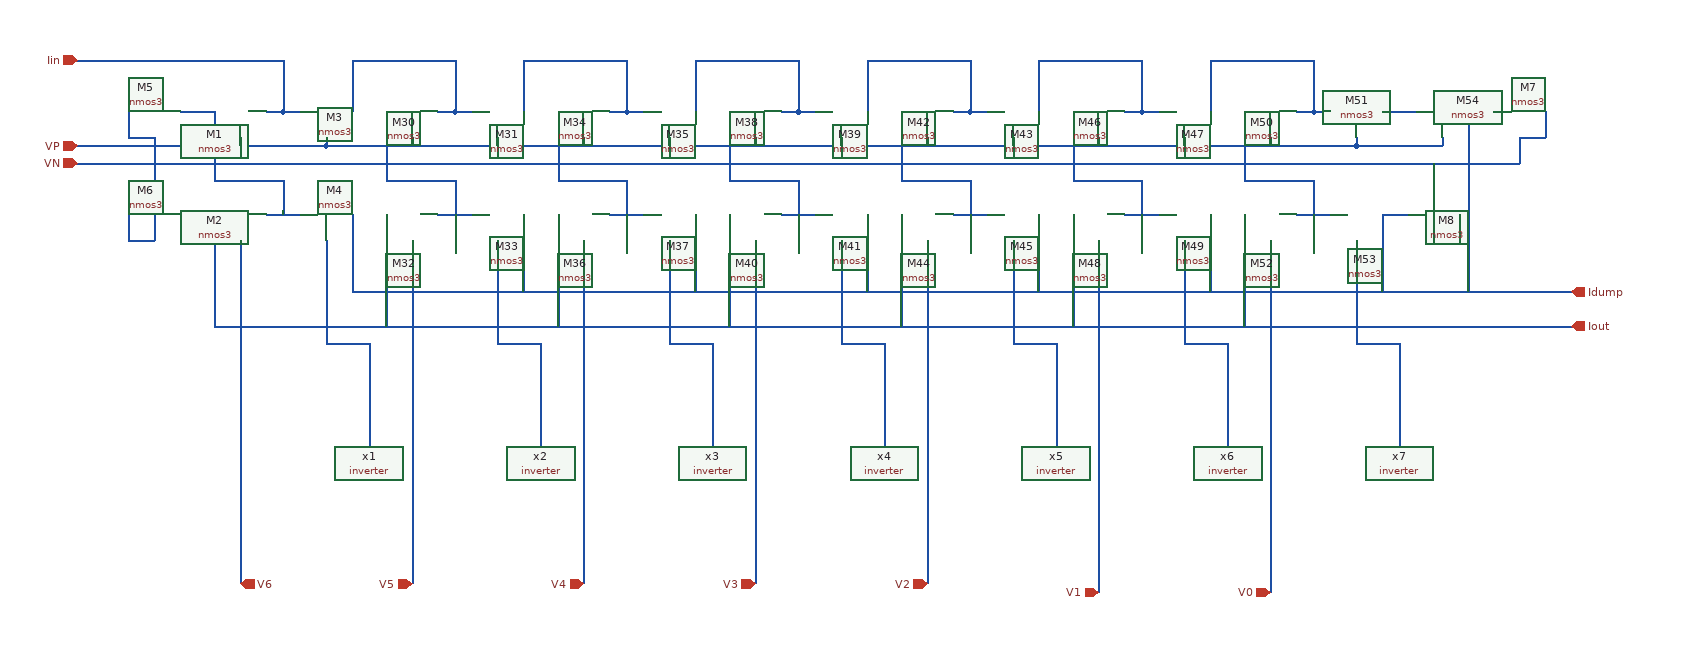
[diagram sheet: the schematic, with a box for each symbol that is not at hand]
v {xschem version=3.4.3 file_version=1.2
}
G {}
K {}
V {}
S {}
E {}
N 650 -40 650 -30 {
lab=V4}
N 250 -30 250 140 {
lab=V6}
N 450 -30 450 140 {
lab=V5}
N 650 -30 650 140 {
lab=V4}
N 850 -30 850 140 {
lab=V3}
N 1050 -30 1050 130 {
lab=V2}
N 1250 -30 1250 130 {
lab=V1}
N 1450 -30 1450 130 {
lab=V0}
N 1050 130 1050 140 {
lab=V2}
N 1250 130 1250 150 {
lab=V1}
N 1450 130 1450 150 {
lab=V0}
N 160 -370 350 -370 {
lab=VP}
N 350 -380 350 -370 {
lab=VP}
N 250 -380 250 -370 {
lab=VP}
N 160 -470 300 -470 {
lab=Iin}
N 300 -470 300 -410 {
lab=Iin}
N 280 -410 300 -410 {
lab=Iin}
N 300 -410 320 -410 {
lab=Iin}
N 280 -290 320 -290 {
lab=#net1}
N 220 -410 220 -330 {
lab=#net1}
N 220 -330 300 -330 {
lab=#net1}
N 300 -330 300 -290 {
lab=#net1}
N 550 -380 550 -370 {
lab=VP}
N 450 -380 450 -370 {
lab=VP}
N 500 -470 500 -410 {
lab=#net2}
N 480 -410 500 -410 {
lab=#net2}
N 500 -410 520 -410 {
lab=#net2}
N 480 -290 520 -290 {
lab=#net3}
N 420 -410 420 -330 {
lab=#net3}
N 420 -330 500 -330 {
lab=#net3}
N 500 -330 500 -290 {
lab=#net3}
N 450 -260 450 -240 {
lab=V5}
N 550 -260 550 -240 {
lab=#net4}
N 380 -470 380 -410 {
lab=#net2}
N 380 -470 500 -470 {
lab=#net2}
N 750 -380 750 -370 {
lab=VP}
N 650 -380 650 -370 {
lab=VP}
N 700 -470 700 -410 {
lab=#net5}
N 680 -410 700 -410 {
lab=#net5}
N 700 -410 720 -410 {
lab=#net5}
N 680 -290 720 -290 {
lab=#net6}
N 620 -410 620 -330 {
lab=#net6}
N 620 -330 700 -330 {
lab=#net6}
N 700 -330 700 -290 {
lab=#net6}
N 650 -260 650 -240 {
lab=V4}
N 750 -260 750 -240 {
lab=#net7}
N 580 -470 580 -410 {
lab=#net5}
N 580 -470 700 -470 {
lab=#net5}
N 950 -380 950 -370 {
lab=VP}
N 850 -380 850 -370 {
lab=VP}
N 900 -470 900 -410 {
lab=#net8}
N 880 -410 900 -410 {
lab=#net8}
N 900 -410 920 -410 {
lab=#net8}
N 880 -290 920 -290 {
lab=#net9}
N 820 -410 820 -330 {
lab=#net9}
N 820 -330 900 -330 {
lab=#net9}
N 900 -330 900 -290 {
lab=#net9}
N 850 -260 850 -240 {
lab=V3}
N 950 -260 950 -240 {
lab=#net10}
N 780 -470 780 -410 {
lab=#net8}
N 780 -470 900 -470 {
lab=#net8}
N 1150 -380 1150 -370 {
lab=VP}
N 1050 -380 1050 -370 {
lab=VP}
N 1100 -470 1100 -410 {
lab=#net11}
N 1080 -410 1100 -410 {
lab=#net11}
N 1100 -410 1120 -410 {
lab=#net11}
N 1080 -290 1120 -290 {
lab=#net12}
N 1020 -410 1020 -330 {
lab=#net12}
N 1020 -330 1100 -330 {
lab=#net12}
N 1100 -330 1100 -290 {
lab=#net12}
N 1050 -260 1050 -240 {
lab=V2}
N 1150 -260 1150 -240 {
lab=#net13}
N 980 -470 980 -410 {
lab=#net11}
N 980 -470 1100 -470 {
lab=#net11}
N 1350 -380 1350 -370 {
lab=VP}
N 1250 -380 1250 -370 {
lab=VP}
N 1300 -470 1300 -410 {
lab=#net14}
N 1280 -410 1300 -410 {
lab=#net14}
N 1300 -410 1320 -410 {
lab=#net14}
N 1280 -290 1320 -290 {
lab=#net15}
N 1220 -410 1220 -330 {
lab=#net15}
N 1220 -330 1300 -330 {
lab=#net15}
N 1300 -330 1300 -290 {
lab=#net15}
N 1250 -260 1250 -240 {
lab=V1}
N 1350 -260 1350 -240 {
lab=#net16}
N 1180 -470 1180 -410 {
lab=#net14}
N 1180 -470 1300 -470 {
lab=#net14}
N 1550 -380 1550 -370 {
lab=VP}
N 1450 -380 1450 -370 {
lab=VP}
N 1500 -470 1500 -410 {
lab=#net17}
N 1480 -410 1500 -410 {
lab=#net17}
N 1500 -410 1520 -410 {
lab=#net17}
N 1480 -290 1520 -290 {
lab=#net18}
N 1420 -410 1420 -330 {
lab=#net18}
N 1420 -330 1500 -330 {
lab=#net18}
N 1500 -330 1500 -290 {
lab=#net18}
N 1450 -260 1450 -240 {
lab=V0}
N 1550 -260 1550 -240 {
lab=#net19}
N 1380 -470 1380 -410 {
lab=#net17}
N 1380 -470 1500 -470 {
lab=#net17}
N 350 -370 1550 -370 {
lab=VP}
N 380 -290 380 -200 {
lab=Idump}
N 380 -200 1620 -200 {
lab=Idump}
N 220 -290 220 -160 {
lab=Iout}
N 350 -260 350 -240 {
lab=#net20}
N 250 -260 250 -240 {
lab=V6}
N 580 -290 580 -200 {
lab=Idump}
N 420 -290 420 -160 {
lab=Iout}
N 780 -290 780 -200 {
lab=Idump}
N 620 -290 620 -160 {
lab=Iout}
N 820 -290 820 -160 {
lab=Iout}
N 980 -290 980 -200 {
lab=Idump}
N 1020 -290 1020 -160 {
lab=Iout}
N 1180 -290 1180 -200 {
lab=Idump}
N 1220 -290 1220 -160 {
lab=Iout}
N 1380 -290 1380 -200 {
lab=Idump}
N 1420 -290 1420 -160 {
lab=Iout}
N 1580 -290 1580 -200 {
lab=Idump}
N 1580 -410 1620 -410 {
lab=#net21}
N 1550 -370 1650 -370 {
lab=VP}
N 1650 -380 1650 -370 {
lab=VP}
N 1620 -200 1700 -200 {
lab=Idump}
N 1620 -160 1700 -160 {
lab=Iout}
N 1680 -410 1680 -200 {
lab=Idump}
N 250 -240 250 -30 {
lab=V6}
N 220 -160 1620 -160 {
lab=Iout}
N 400 -140 400 -20 {
lab=#net20}
N 350 -140 400 -140 {
lab=#net20}
N 350 -240 350 -140 {
lab=#net20}
N 450 -240 450 -30 {
lab=V5}
N 550 -240 550 -140 {
lab=#net4}
N 550 -140 600 -140 {
lab=#net4}
N 600 -140 600 -20 {
lab=#net4}
N 650 -240 650 -40 {
lab=V4}
N 800 -140 800 -20 {
lab=#net7}
N 750 -140 800 -140 {
lab=#net7}
N 750 -240 750 -140 {
lab=#net7}
N 850 -240 850 -30 {
lab=V3}
N 1000 -140 1000 -20 {
lab=#net10}
N 950 -140 1000 -140 {
lab=#net10}
N 950 -240 950 -140 {
lab=#net10}
N 1050 -240 1050 -30 {
lab=V2}
N 1200 -140 1200 -20 {
lab=#net13}
N 1150 -140 1200 -140 {
lab=#net13}
N 1150 -240 1150 -140 {
lab=#net13}
N 1250 -240 1250 -30 {
lab=V1}
N 1400 -140 1400 -20 {
lab=#net16}
N 1350 -140 1400 -140 {
lab=#net16}
N 1350 -240 1350 -140 {
lab=#net16}
N 1450 -240 1450 -30 {
lab=V0}
N 1600 -140 1600 -20 {
lab=#net19}
N 1550 -140 1600 -140 {
lab=#net19}
N 1550 -240 1550 -140 {
lab=#net19}
N 120 -380 150 -380 {
lab=#net22}
N 120 -410 120 -380 {
lab=#net22}
N 180 -410 220 -410 {
lab=#net1}
N 120 -260 150 -260 {
lab=#net23}
N 120 -290 120 -260 {
lab=#net23}
N 180 -290 220 -290 {
lab=Iout}
N 60 -370 160 -370 {
lab=VP}
N 60 -470 160 -470 {
lab=Iin}
N 1680 -410 1710 -410 {
lab=Idump}
N 1740 -380 1770 -380 {
lab=#net24}
N 1770 -410 1770 -380 {
lab=#net24}
N 1580 -290 1610 -290 {
lab=Idump}
N 1640 -260 1670 -260 {
lab=#net25}
N 1670 -290 1670 -260 {
lab=#net25}
N 1700 -200 1800 -200 {
lab=Idump}
N 1700 -160 1800 -160 {
lab=Iout}
N 60 -350 1740 -350 {}
N 1740 -380 1740 -350 {}
N 1640 -350 1640 -260 {}
N 150 -380 150 -350 {}
N 150 -350 150 -260 {}
C {madvlsi/nmos3.sym} 250 -410 1 1 {name=M1
L=8

body=GND
nf=1
mult=1
ad="'int((nf+1)/2) * W/nf * 0.29'" 
pd="'2*int((nf+1)/2) * (W/nf + 0.29)'"
as="'int((nf+2)/2) * W/nf * 0.29'" 
ps="'2*int((nf+2)/2) * (W/nf + 0.29)'"
nrd="'0.29 / W'" nrs="'0.29 / W'"
sa=0 sb=0 sd=0
model=nfet_01v8
spiceprefix=X
W=24}
C {madvlsi/nmos3.sym} 350 -410 3 0 {name=M3
L=8

body=GND
nf=1
mult=1
ad="'int((nf+1)/2) * W/nf * 0.29'" 
pd="'2*int((nf+1)/2) * (W/nf + 0.29)'"
as="'int((nf+2)/2) * W/nf * 0.29'" 
ps="'2*int((nf+2)/2) * (W/nf + 0.29)'"
nrd="'0.29 / W'" nrs="'0.29 / W'"
sa=0 sb=0 sd=0
model=nfet_01v8
spiceprefix=X
W=24}
C {madvlsi/nmos3.sym} 250 -290 1 1 {name=M2
L=8

body=GND
nf=1
mult=1
ad="'int((nf+1)/2) * W/nf * 0.29'" 
pd="'2*int((nf+1)/2) * (W/nf + 0.29)'"
as="'int((nf+2)/2) * W/nf * 0.29'" 
ps="'2*int((nf+2)/2) * (W/nf + 0.29)'"
nrd="'0.29 / W'" nrs="'0.29 / W'"
sa=0 sb=0 sd=0
model=nfet_01v8
spiceprefix=X
W=24}
C {madvlsi/nmos3.sym} 350 -290 3 0 {name=M4
L=8

body=GND
nf=1
mult=1
ad="'int((nf+1)/2) * W/nf * 0.29'" 
pd="'2*int((nf+1)/2) * (W/nf + 0.29)'"
as="'int((nf+2)/2) * W/nf * 0.29'" 
ps="'2*int((nf+2)/2) * (W/nf + 0.29)'"
nrd="'0.29 / W'" nrs="'0.29 / W'"
sa=0 sb=0 sd=0
model=nfet_01v8
spiceprefix=X
W=24}
C {devices/ipin.sym} 250 140 1 1 {name=p4 lab=V6}
C {devices/ipin.sym} 450 140 3 0 {name=p6 lab=V5}
C {devices/ipin.sym} 650 140 3 0 {name=p7 lab=V4}
C {devices/ipin.sym} 850 140 3 0 {name=p8 lab=V3}
C {devices/ipin.sym} 1050 140 3 0 {name=p9 lab=V2}
C {devices/ipin.sym} 1250 150 3 0 {name=p10 lab=V1}
C {devices/ipin.sym} 1450 150 3 0 {name=p11 lab=V0}
C {./inverter.sym} 360 -20 0 0 {name=x1}
C {./inverter.sym} 560 -20 0 0 {name=x2}
C {./inverter.sym} 760 -20 0 0 {name=x3}
C {./inverter.sym} 960 -20 0 0 {name=x4}
C {./inverter.sym} 1160 -20 0 0 {name=x5}
C {./inverter.sym} 1360 -20 0 0 {name=x6}
C {./inverter.sym} 1560 -20 0 0 {name=x7}
C {devices/iopin.sym} 60 -470 2 0 {name=p1 lab=Iin}
C {devices/iopin.sym} 60 -370 2 0 {name=p13 lab=VP}
C {madvlsi/nmos3.sym} 450 -410 1 1 {name=M30
L=8

body=GND
nf=1
mult=1
ad="'int((nf+1)/2) * W/nf * 0.29'" 
pd="'2*int((nf+1)/2) * (W/nf + 0.29)'"
as="'int((nf+2)/2) * W/nf * 0.29'" 
ps="'2*int((nf+2)/2) * (W/nf + 0.29)'"
nrd="'0.29 / W'" nrs="'0.29 / W'"
sa=0 sb=0 sd=0
model=nfet_01v8
spiceprefix=X
W=24}
C {madvlsi/nmos3.sym} 550 -410 3 0 {name=M31
L=8

body=GND
nf=1
mult=1
ad="'int((nf+1)/2) * W/nf * 0.29'" 
pd="'2*int((nf+1)/2) * (W/nf + 0.29)'"
as="'int((nf+2)/2) * W/nf * 0.29'" 
ps="'2*int((nf+2)/2) * (W/nf + 0.29)'"
nrd="'0.29 / W'" nrs="'0.29 / W'"
sa=0 sb=0 sd=0
model=nfet_01v8
spiceprefix=X
W=24}
C {madvlsi/nmos3.sym} 450 -290 1 1 {name=M32
L=8

body=GND
nf=1
mult=1
ad="'int((nf+1)/2) * W/nf * 0.29'" 
pd="'2*int((nf+1)/2) * (W/nf + 0.29)'"
as="'int((nf+2)/2) * W/nf * 0.29'" 
ps="'2*int((nf+2)/2) * (W/nf + 0.29)'"
nrd="'0.29 / W'" nrs="'0.29 / W'"
sa=0 sb=0 sd=0
model=nfet_01v8
spiceprefix=X
W=24}
C {madvlsi/nmos3.sym} 550 -290 3 0 {name=M33
L=8

body=GND
nf=1
mult=1
ad="'int((nf+1)/2) * W/nf * 0.29'" 
pd="'2*int((nf+1)/2) * (W/nf + 0.29)'"
as="'int((nf+2)/2) * W/nf * 0.29'" 
ps="'2*int((nf+2)/2) * (W/nf + 0.29)'"
nrd="'0.29 / W'" nrs="'0.29 / W'"
sa=0 sb=0 sd=0
model=nfet_01v8
spiceprefix=X
W=24}
C {madvlsi/nmos3.sym} 650 -410 1 1 {name=M34
L=8

body=GND
nf=1
mult=1
ad="'int((nf+1)/2) * W/nf * 0.29'" 
pd="'2*int((nf+1)/2) * (W/nf + 0.29)'"
as="'int((nf+2)/2) * W/nf * 0.29'" 
ps="'2*int((nf+2)/2) * (W/nf + 0.29)'"
nrd="'0.29 / W'" nrs="'0.29 / W'"
sa=0 sb=0 sd=0
model=nfet_01v8
spiceprefix=X
W=24}
C {madvlsi/nmos3.sym} 750 -410 3 0 {name=M35
L=8

body=GND
nf=1
mult=1
ad="'int((nf+1)/2) * W/nf * 0.29'" 
pd="'2*int((nf+1)/2) * (W/nf + 0.29)'"
as="'int((nf+2)/2) * W/nf * 0.29'" 
ps="'2*int((nf+2)/2) * (W/nf + 0.29)'"
nrd="'0.29 / W'" nrs="'0.29 / W'"
sa=0 sb=0 sd=0
model=nfet_01v8
spiceprefix=X
W=24}
C {madvlsi/nmos3.sym} 650 -290 1 1 {name=M36
L=8

body=GND
nf=1
mult=1
ad="'int((nf+1)/2) * W/nf * 0.29'" 
pd="'2*int((nf+1)/2) * (W/nf + 0.29)'"
as="'int((nf+2)/2) * W/nf * 0.29'" 
ps="'2*int((nf+2)/2) * (W/nf + 0.29)'"
nrd="'0.29 / W'" nrs="'0.29 / W'"
sa=0 sb=0 sd=0
model=nfet_01v8
spiceprefix=X
W=24}
C {madvlsi/nmos3.sym} 750 -290 3 0 {name=M37
L=8

body=GND
nf=1
mult=1
ad="'int((nf+1)/2) * W/nf * 0.29'" 
pd="'2*int((nf+1)/2) * (W/nf + 0.29)'"
as="'int((nf+2)/2) * W/nf * 0.29'" 
ps="'2*int((nf+2)/2) * (W/nf + 0.29)'"
nrd="'0.29 / W'" nrs="'0.29 / W'"
sa=0 sb=0 sd=0
model=nfet_01v8
spiceprefix=X
W=24}
C {madvlsi/nmos3.sym} 850 -410 1 1 {name=M38
L=8

body=GND
nf=1
mult=1
ad="'int((nf+1)/2) * W/nf * 0.29'" 
pd="'2*int((nf+1)/2) * (W/nf + 0.29)'"
as="'int((nf+2)/2) * W/nf * 0.29'" 
ps="'2*int((nf+2)/2) * (W/nf + 0.29)'"
nrd="'0.29 / W'" nrs="'0.29 / W'"
sa=0 sb=0 sd=0
model=nfet_01v8
spiceprefix=X
W=24}
C {madvlsi/nmos3.sym} 950 -410 3 0 {name=M39
L=8

body=GND
nf=1
mult=1
ad="'int((nf+1)/2) * W/nf * 0.29'" 
pd="'2*int((nf+1)/2) * (W/nf + 0.29)'"
as="'int((nf+2)/2) * W/nf * 0.29'" 
ps="'2*int((nf+2)/2) * (W/nf + 0.29)'"
nrd="'0.29 / W'" nrs="'0.29 / W'"
sa=0 sb=0 sd=0
model=nfet_01v8
spiceprefix=X
W=24}
C {madvlsi/nmos3.sym} 850 -290 1 1 {name=M40
L=8

body=GND
nf=1
mult=1
ad="'int((nf+1)/2) * W/nf * 0.29'" 
pd="'2*int((nf+1)/2) * (W/nf + 0.29)'"
as="'int((nf+2)/2) * W/nf * 0.29'" 
ps="'2*int((nf+2)/2) * (W/nf + 0.29)'"
nrd="'0.29 / W'" nrs="'0.29 / W'"
sa=0 sb=0 sd=0
model=nfet_01v8
spiceprefix=X
W=24}
C {madvlsi/nmos3.sym} 950 -290 3 0 {name=M41
L=8

body=GND
nf=1
mult=1
ad="'int((nf+1)/2) * W/nf * 0.29'" 
pd="'2*int((nf+1)/2) * (W/nf + 0.29)'"
as="'int((nf+2)/2) * W/nf * 0.29'" 
ps="'2*int((nf+2)/2) * (W/nf + 0.29)'"
nrd="'0.29 / W'" nrs="'0.29 / W'"
sa=0 sb=0 sd=0
model=nfet_01v8
spiceprefix=X
W=24}
C {madvlsi/nmos3.sym} 1050 -410 1 1 {name=M42
L=8

body=GND
nf=1
mult=1
ad="'int((nf+1)/2) * W/nf * 0.29'" 
pd="'2*int((nf+1)/2) * (W/nf + 0.29)'"
as="'int((nf+2)/2) * W/nf * 0.29'" 
ps="'2*int((nf+2)/2) * (W/nf + 0.29)'"
nrd="'0.29 / W'" nrs="'0.29 / W'"
sa=0 sb=0 sd=0
model=nfet_01v8
spiceprefix=X
W=24}
C {madvlsi/nmos3.sym} 1150 -410 3 0 {name=M43
L=8

body=GND
nf=1
mult=1
ad="'int((nf+1)/2) * W/nf * 0.29'" 
pd="'2*int((nf+1)/2) * (W/nf + 0.29)'"
as="'int((nf+2)/2) * W/nf * 0.29'" 
ps="'2*int((nf+2)/2) * (W/nf + 0.29)'"
nrd="'0.29 / W'" nrs="'0.29 / W'"
sa=0 sb=0 sd=0
model=nfet_01v8
spiceprefix=X
W=24}
C {madvlsi/nmos3.sym} 1050 -290 1 1 {name=M44
L=8

body=GND
nf=1
mult=1
ad="'int((nf+1)/2) * W/nf * 0.29'" 
pd="'2*int((nf+1)/2) * (W/nf + 0.29)'"
as="'int((nf+2)/2) * W/nf * 0.29'" 
ps="'2*int((nf+2)/2) * (W/nf + 0.29)'"
nrd="'0.29 / W'" nrs="'0.29 / W'"
sa=0 sb=0 sd=0
model=nfet_01v8
spiceprefix=X
W=24}
C {madvlsi/nmos3.sym} 1150 -290 3 0 {name=M45
L=8

body=GND
nf=1
mult=1
ad="'int((nf+1)/2) * W/nf * 0.29'" 
pd="'2*int((nf+1)/2) * (W/nf + 0.29)'"
as="'int((nf+2)/2) * W/nf * 0.29'" 
ps="'2*int((nf+2)/2) * (W/nf + 0.29)'"
nrd="'0.29 / W'" nrs="'0.29 / W'"
sa=0 sb=0 sd=0
model=nfet_01v8
spiceprefix=X
W=24}
C {madvlsi/nmos3.sym} 1250 -410 1 1 {name=M46
L=8

body=GND
nf=1
mult=1
ad="'int((nf+1)/2) * W/nf * 0.29'" 
pd="'2*int((nf+1)/2) * (W/nf + 0.29)'"
as="'int((nf+2)/2) * W/nf * 0.29'" 
ps="'2*int((nf+2)/2) * (W/nf + 0.29)'"
nrd="'0.29 / W'" nrs="'0.29 / W'"
sa=0 sb=0 sd=0
model=nfet_01v8
spiceprefix=X
W=24}
C {madvlsi/nmos3.sym} 1350 -410 3 0 {name=M47
L=8

body=GND
nf=1
mult=1
ad="'int((nf+1)/2) * W/nf * 0.29'" 
pd="'2*int((nf+1)/2) * (W/nf + 0.29)'"
as="'int((nf+2)/2) * W/nf * 0.29'" 
ps="'2*int((nf+2)/2) * (W/nf + 0.29)'"
nrd="'0.29 / W'" nrs="'0.29 / W'"
sa=0 sb=0 sd=0
model=nfet_01v8
spiceprefix=X
W=24}
C {madvlsi/nmos3.sym} 1250 -290 1 1 {name=M48
L=8

body=GND
nf=1
mult=1
ad="'int((nf+1)/2) * W/nf * 0.29'" 
pd="'2*int((nf+1)/2) * (W/nf + 0.29)'"
as="'int((nf+2)/2) * W/nf * 0.29'" 
ps="'2*int((nf+2)/2) * (W/nf + 0.29)'"
nrd="'0.29 / W'" nrs="'0.29 / W'"
sa=0 sb=0 sd=0
model=nfet_01v8
spiceprefix=X
W=24}
C {madvlsi/nmos3.sym} 1350 -290 3 0 {name=M49
L=8

body=GND
nf=1
mult=1
ad="'int((nf+1)/2) * W/nf * 0.29'" 
pd="'2*int((nf+1)/2) * (W/nf + 0.29)'"
as="'int((nf+2)/2) * W/nf * 0.29'" 
ps="'2*int((nf+2)/2) * (W/nf + 0.29)'"
nrd="'0.29 / W'" nrs="'0.29 / W'"
sa=0 sb=0 sd=0
model=nfet_01v8
spiceprefix=X
W=24}
C {madvlsi/nmos3.sym} 1450 -410 1 1 {name=M50
L=8

body=GND
nf=1
mult=1
ad="'int((nf+1)/2) * W/nf * 0.29'" 
pd="'2*int((nf+1)/2) * (W/nf + 0.29)'"
as="'int((nf+2)/2) * W/nf * 0.29'" 
ps="'2*int((nf+2)/2) * (W/nf + 0.29)'"
nrd="'0.29 / W'" nrs="'0.29 / W'"
sa=0 sb=0 sd=0
model=nfet_01v8
spiceprefix=X
W=24}
C {madvlsi/nmos3.sym} 1550 -410 3 0 {name=M51
L=8

body=GND
nf=1
mult=1
ad="'int((nf+1)/2) * W/nf * 0.29'" 
pd="'2*int((nf+1)/2) * (W/nf + 0.29)'"
as="'int((nf+2)/2) * W/nf * 0.29'" 
ps="'2*int((nf+2)/2) * (W/nf + 0.29)'"
nrd="'0.29 / W'" nrs="'0.29 / W'"
sa=0 sb=0 sd=0
model=nfet_01v8
spiceprefix=X
W=24}
C {madvlsi/nmos3.sym} 1450 -290 1 1 {name=M52
L=8

body=GND
nf=1
mult=1
ad="'int((nf+1)/2) * W/nf * 0.29'" 
pd="'2*int((nf+1)/2) * (W/nf + 0.29)'"
as="'int((nf+2)/2) * W/nf * 0.29'" 
ps="'2*int((nf+2)/2) * (W/nf + 0.29)'"
nrd="'0.29 / W'" nrs="'0.29 / W'"
sa=0 sb=0 sd=0
model=nfet_01v8
spiceprefix=X
W=24}
C {madvlsi/nmos3.sym} 1550 -290 3 0 {name=M53
L=8

body=GND
nf=1
mult=1
ad="'int((nf+1)/2) * W/nf * 0.29'" 
pd="'2*int((nf+1)/2) * (W/nf + 0.29)'"
as="'int((nf+2)/2) * W/nf * 0.29'" 
ps="'2*int((nf+2)/2) * (W/nf + 0.29)'"
nrd="'0.29 / W'" nrs="'0.29 / W'"
sa=0 sb=0 sd=0
model=nfet_01v8
spiceprefix=X
W=24}
C {devices/opin.sym} 1800 -200 0 0 {name=p14 lab=Idump}
C {devices/opin.sym} 1800 -160 0 0 {name=p15 lab=Iout}
C {madvlsi/nmos3.sym} 1650 -410 3 0 {name=M54
L=8

body=GND
nf=1
mult=1
ad="'int((nf+1)/2) * W/nf * 0.29'" 
pd="'2*int((nf+1)/2) * (W/nf + 0.29)'"
as="'int((nf+2)/2) * W/nf * 0.29'" 
ps="'2*int((nf+2)/2) * (W/nf + 0.29)'"
nrd="'0.29 / W'" nrs="'0.29 / W'"
sa=0 sb=0 sd=0
model=nfet_01v8
spiceprefix=X
W=24}
C {madvlsi/nmos3.sym} 150 -410 3 0 {name=M5
L=8

body=GND
nf=1
mult=1
ad="'int((nf+1)/2) * W/nf * 0.29'" 
pd="'2*int((nf+1)/2) * (W/nf + 0.29)'"
as="'int((nf+2)/2) * W/nf * 0.29'" 
ps="'2*int((nf+2)/2) * (W/nf + 0.29)'"
nrd="'0.29 / W'" nrs="'0.29 / W'"
sa=0 sb=0 sd=0
model=nfet_01v8
spiceprefix=X
W=24}
C {madvlsi/nmos3.sym} 150 -290 3 0 {name=M6
L=8

body=GND
nf=1
mult=1
ad="'int((nf+1)/2) * W/nf * 0.29'" 
pd="'2*int((nf+1)/2) * (W/nf + 0.29)'"
as="'int((nf+2)/2) * W/nf * 0.29'" 
ps="'2*int((nf+2)/2) * (W/nf + 0.29)'"
nrd="'0.29 / W'" nrs="'0.29 / W'"
sa=0 sb=0 sd=0
model=nfet_01v8
spiceprefix=X
W=24}
C {madvlsi/nmos3.sym} 1740 -410 1 1 {name=M7
L=8

body=GND
nf=1
mult=1
ad="'int((nf+1)/2) * W/nf * 0.29'" 
pd="'2*int((nf+1)/2) * (W/nf + 0.29)'"
as="'int((nf+2)/2) * W/nf * 0.29'" 
ps="'2*int((nf+2)/2) * (W/nf + 0.29)'"
nrd="'0.29 / W'" nrs="'0.29 / W'"
sa=0 sb=0 sd=0
model=nfet_01v8
spiceprefix=X
W=24}
C {madvlsi/nmos3.sym} 1640 -290 1 1 {name=M8
L=8

body=GND
nf=1
mult=1
ad="'int((nf+1)/2) * W/nf * 0.29'" 
pd="'2*int((nf+1)/2) * (W/nf + 0.29)'"
as="'int((nf+2)/2) * W/nf * 0.29'" 
ps="'2*int((nf+2)/2) * (W/nf + 0.29)'"
nrd="'0.29 / W'" nrs="'0.29 / W'"
sa=0 sb=0 sd=0
model=nfet_01v8
spiceprefix=X
W=24}
C {devices/iopin.sym} 60 -350 2 0 {name=p2 lab=VN}
